VERSION 5.8 ;
BUSBITCHARS "[]" ;
DIVIDERCHAR "/" ;
UNITS
    DATABASE MICRONS 1000 ;
END UNITS

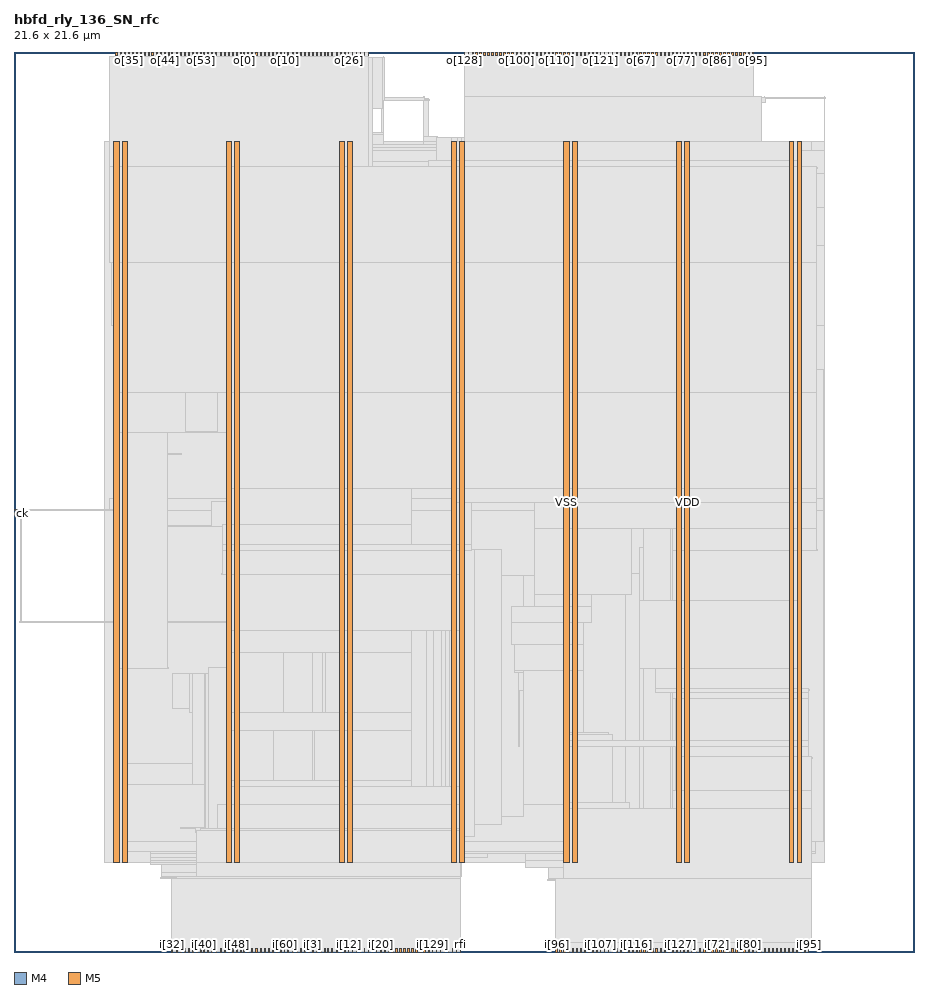
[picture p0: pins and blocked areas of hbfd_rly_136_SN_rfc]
MACRO hbfd_rly_136_SN_rfc
  FOREIGN hbfd_rly_136_SN_rfc 0 0 ;
  CLASS BLOCK ;
  SIZE 21.6 BY 21.6 ;
  PIN ck
    DIRECTION INPUT ;
    USE SIGNAL ;
    PORT
      LAYER M4 ;
        RECT  0 10.512 0.084 10.536 ;
    END
  END ck
  PIN i[0]
    DIRECTION INPUT ;
    USE SIGNAL ;
    PORT
      LAYER M5 ;
        RECT  6.864 0 6.888 0.084 ;
    END
  END i[0]
  PIN i[100]
    DIRECTION INPUT ;
    USE SIGNAL ;
    PORT
      LAYER M5 ;
        RECT  13.392 0 13.416 0.084 ;
    END
  END i[100]
  PIN i[101]
    DIRECTION INPUT ;
    USE SIGNAL ;
    PORT
      LAYER M5 ;
        RECT  13.488 0 13.512 0.084 ;
    END
  END i[101]
  PIN i[102]
    DIRECTION INPUT ;
    USE SIGNAL ;
    PORT
      LAYER M5 ;
        RECT  13.584 0 13.608 0.084 ;
    END
  END i[102]
  PIN i[103]
    DIRECTION INPUT ;
    USE SIGNAL ;
    PORT
      LAYER M5 ;
        RECT  13.68 0 13.704 0.084 ;
    END
  END i[103]
  PIN i[104]
    DIRECTION INPUT ;
    USE SIGNAL ;
    PORT
      LAYER M5 ;
        RECT  13.776 0 13.8 0.084 ;
    END
  END i[104]
  PIN i[105]
    DIRECTION INPUT ;
    USE SIGNAL ;
    PORT
      LAYER M5 ;
        RECT  13.872 0 13.896 0.084 ;
    END
  END i[105]
  PIN i[106]
    DIRECTION INPUT ;
    USE SIGNAL ;
    PORT
      LAYER M5 ;
        RECT  13.968 0 13.992 0.084 ;
    END
  END i[106]
  PIN i[107]
    DIRECTION INPUT ;
    USE SIGNAL ;
    PORT
      LAYER M5 ;
        RECT  14.064 0 14.088 0.084 ;
    END
  END i[107]
  PIN i[108]
    DIRECTION INPUT ;
    USE SIGNAL ;
    PORT
      LAYER M5 ;
        RECT  14.16 0 14.184 0.084 ;
    END
  END i[108]
  PIN i[109]
    DIRECTION INPUT ;
    USE SIGNAL ;
    PORT
      LAYER M5 ;
        RECT  14.256 0 14.28 0.084 ;
    END
  END i[109]
  PIN i[10]
    DIRECTION INPUT ;
    USE SIGNAL ;
    PORT
      LAYER M5 ;
        RECT  7.824 0 7.848 0.084 ;
    END
  END i[10]
  PIN i[110]
    DIRECTION INPUT ;
    USE SIGNAL ;
    PORT
      LAYER M5 ;
        RECT  14.352 0 14.376 0.084 ;
    END
  END i[110]
  PIN i[111]
    DIRECTION INPUT ;
    USE SIGNAL ;
    PORT
      LAYER M5 ;
        RECT  14.448 0 14.472 0.084 ;
    END
  END i[111]
  PIN i[112]
    DIRECTION INPUT ;
    USE SIGNAL ;
    PORT
      LAYER M5 ;
        RECT  14.544 0 14.568 0.084 ;
    END
  END i[112]
  PIN i[113]
    DIRECTION INPUT ;
    USE SIGNAL ;
    PORT
      LAYER M5 ;
        RECT  14.64 0 14.664 0.084 ;
    END
  END i[113]
  PIN i[114]
    DIRECTION INPUT ;
    USE SIGNAL ;
    PORT
      LAYER M5 ;
        RECT  14.736 0 14.76 0.084 ;
    END
  END i[114]
  PIN i[115]
    DIRECTION INPUT ;
    USE SIGNAL ;
    PORT
      LAYER M5 ;
        RECT  14.832 0 14.856 0.084 ;
    END
  END i[115]
  PIN i[116]
    DIRECTION INPUT ;
    USE SIGNAL ;
    PORT
      LAYER M5 ;
        RECT  14.928 0 14.952 0.084 ;
    END
  END i[116]
  PIN i[117]
    DIRECTION INPUT ;
    USE SIGNAL ;
    PORT
      LAYER M5 ;
        RECT  15.024 0 15.048 0.084 ;
    END
  END i[117]
  PIN i[118]
    DIRECTION INPUT ;
    USE SIGNAL ;
    PORT
      LAYER M5 ;
        RECT  15.12 0 15.144 0.084 ;
    END
  END i[118]
  PIN i[119]
    DIRECTION INPUT ;
    USE SIGNAL ;
    PORT
      LAYER M5 ;
        RECT  15.216 0 15.24 0.084 ;
    END
  END i[119]
  PIN i[11]
    DIRECTION INPUT ;
    USE SIGNAL ;
    PORT
      LAYER M5 ;
        RECT  7.92 0 7.944 0.084 ;
    END
  END i[11]
  PIN i[120]
    DIRECTION INPUT ;
    USE SIGNAL ;
    PORT
      LAYER M5 ;
        RECT  15.312 0 15.336 0.084 ;
    END
  END i[120]
  PIN i[121]
    DIRECTION INPUT ;
    USE SIGNAL ;
    PORT
      LAYER M5 ;
        RECT  15.408 0 15.432 0.084 ;
    END
  END i[121]
  PIN i[122]
    DIRECTION INPUT ;
    USE SIGNAL ;
    PORT
      LAYER M5 ;
        RECT  15.504 0 15.528 0.084 ;
    END
  END i[122]
  PIN i[123]
    DIRECTION INPUT ;
    USE SIGNAL ;
    PORT
      LAYER M5 ;
        RECT  15.6 0 15.624 0.084 ;
    END
  END i[123]
  PIN i[124]
    DIRECTION INPUT ;
    USE SIGNAL ;
    PORT
      LAYER M5 ;
        RECT  15.696 0 15.72 0.084 ;
    END
  END i[124]
  PIN i[125]
    DIRECTION INPUT ;
    USE SIGNAL ;
    PORT
      LAYER M5 ;
        RECT  15.792 0 15.816 0.084 ;
    END
  END i[125]
  PIN i[126]
    DIRECTION INPUT ;
    USE SIGNAL ;
    PORT
      LAYER M5 ;
        RECT  15.888 0 15.912 0.084 ;
    END
  END i[126]
  PIN i[127]
    DIRECTION INPUT ;
    USE SIGNAL ;
    PORT
      LAYER M5 ;
        RECT  15.984 0 16.008 0.084 ;
    END
  END i[127]
  PIN i[128]
    DIRECTION INPUT ;
    USE SIGNAL ;
    PORT
      LAYER M5 ;
        RECT  9.936 0 9.96 0.084 ;
    END
  END i[128]
  PIN i[129]
    DIRECTION INPUT ;
    USE SIGNAL ;
    PORT
      LAYER M5 ;
        RECT  10.032 0 10.056 0.084 ;
    END
  END i[129]
  PIN i[12]
    DIRECTION INPUT ;
    USE SIGNAL ;
    PORT
      LAYER M5 ;
        RECT  8.016 0 8.04 0.084 ;
    END
  END i[12]
  PIN i[130]
    DIRECTION INPUT ;
    USE SIGNAL ;
    PORT
      LAYER M5 ;
        RECT  10.128 0 10.152 0.084 ;
    END
  END i[130]
  PIN i[131]
    DIRECTION INPUT ;
    USE SIGNAL ;
    PORT
      LAYER M5 ;
        RECT  10.224 0 10.248 0.084 ;
    END
  END i[131]
  PIN i[132]
    DIRECTION INPUT ;
    USE SIGNAL ;
    PORT
      LAYER M5 ;
        RECT  10.32 0 10.344 0.084 ;
    END
  END i[132]
  PIN i[133]
    DIRECTION INPUT ;
    USE SIGNAL ;
    PORT
      LAYER M5 ;
        RECT  10.416 0 10.44 0.084 ;
    END
  END i[133]
  PIN i[134]
    DIRECTION INPUT ;
    USE SIGNAL ;
    PORT
      LAYER M5 ;
        RECT  10.512 0 10.536 0.084 ;
    END
  END i[134]
  PIN i[135]
    DIRECTION INPUT ;
    USE SIGNAL ;
    PORT
      LAYER M5 ;
        RECT  10.608 0 10.632 0.084 ;
    END
  END i[135]
  PIN i[13]
    DIRECTION INPUT ;
    USE SIGNAL ;
    PORT
      LAYER M5 ;
        RECT  8.112 0 8.136 0.084 ;
    END
  END i[13]
  PIN i[14]
    DIRECTION INPUT ;
    USE SIGNAL ;
    PORT
      LAYER M5 ;
        RECT  8.208 0 8.232 0.084 ;
    END
  END i[14]
  PIN i[15]
    DIRECTION INPUT ;
    USE SIGNAL ;
    PORT
      LAYER M5 ;
        RECT  8.304 0 8.328 0.084 ;
    END
  END i[15]
  PIN i[16]
    DIRECTION INPUT ;
    USE SIGNAL ;
    PORT
      LAYER M5 ;
        RECT  8.4 0 8.424 0.084 ;
    END
  END i[16]
  PIN i[17]
    DIRECTION INPUT ;
    USE SIGNAL ;
    PORT
      LAYER M5 ;
        RECT  8.496 0 8.52 0.084 ;
    END
  END i[17]
  PIN i[18]
    DIRECTION INPUT ;
    USE SIGNAL ;
    PORT
      LAYER M5 ;
        RECT  8.592 0 8.616 0.084 ;
    END
  END i[18]
  PIN i[19]
    DIRECTION INPUT ;
    USE SIGNAL ;
    PORT
      LAYER M5 ;
        RECT  8.688 0 8.712 0.084 ;
    END
  END i[19]
  PIN i[1]
    DIRECTION INPUT ;
    USE SIGNAL ;
    PORT
      LAYER M5 ;
        RECT  6.96 0 6.984 0.084 ;
    END
  END i[1]
  PIN i[20]
    DIRECTION INPUT ;
    USE SIGNAL ;
    PORT
      LAYER M5 ;
        RECT  8.784 0 8.808 0.084 ;
    END
  END i[20]
  PIN i[21]
    DIRECTION INPUT ;
    USE SIGNAL ;
    PORT
      LAYER M5 ;
        RECT  8.88 0 8.904 0.084 ;
    END
  END i[21]
  PIN i[22]
    DIRECTION INPUT ;
    USE SIGNAL ;
    PORT
      LAYER M5 ;
        RECT  8.976 0 9 0.084 ;
    END
  END i[22]
  PIN i[23]
    DIRECTION INPUT ;
    USE SIGNAL ;
    PORT
      LAYER M5 ;
        RECT  9.072 0 9.096 0.084 ;
    END
  END i[23]
  PIN i[24]
    DIRECTION INPUT ;
    USE SIGNAL ;
    PORT
      LAYER M5 ;
        RECT  9.168 0 9.192 0.084 ;
    END
  END i[24]
  PIN i[25]
    DIRECTION INPUT ;
    USE SIGNAL ;
    PORT
      LAYER M5 ;
        RECT  9.264 0 9.288 0.084 ;
    END
  END i[25]
  PIN i[26]
    DIRECTION INPUT ;
    USE SIGNAL ;
    PORT
      LAYER M5 ;
        RECT  9.36 0 9.384 0.084 ;
    END
  END i[26]
  PIN i[27]
    DIRECTION INPUT ;
    USE SIGNAL ;
    PORT
      LAYER M5 ;
        RECT  9.456 0 9.48 0.084 ;
    END
  END i[27]
  PIN i[28]
    DIRECTION INPUT ;
    USE SIGNAL ;
    PORT
      LAYER M5 ;
        RECT  9.552 0 9.576 0.084 ;
    END
  END i[28]
  PIN i[29]
    DIRECTION INPUT ;
    USE SIGNAL ;
    PORT
      LAYER M5 ;
        RECT  9.648 0 9.672 0.084 ;
    END
  END i[29]
  PIN i[2]
    DIRECTION INPUT ;
    USE SIGNAL ;
    PORT
      LAYER M5 ;
        RECT  7.056 0 7.08 0.084 ;
    END
  END i[2]
  PIN i[30]
    DIRECTION INPUT ;
    USE SIGNAL ;
    PORT
      LAYER M5 ;
        RECT  9.744 0 9.768 0.084 ;
    END
  END i[30]
  PIN i[31]
    DIRECTION INPUT ;
    USE SIGNAL ;
    PORT
      LAYER M5 ;
        RECT  9.84 0 9.864 0.084 ;
    END
  END i[31]
  PIN i[32]
    DIRECTION INPUT ;
    USE SIGNAL ;
    PORT
      LAYER M5 ;
        RECT  3.792 0 3.816 0.084 ;
    END
  END i[32]
  PIN i[33]
    DIRECTION INPUT ;
    USE SIGNAL ;
    PORT
      LAYER M5 ;
        RECT  3.888 0 3.912 0.084 ;
    END
  END i[33]
  PIN i[34]
    DIRECTION INPUT ;
    USE SIGNAL ;
    PORT
      LAYER M5 ;
        RECT  3.984 0 4.008 0.084 ;
    END
  END i[34]
  PIN i[35]
    DIRECTION INPUT ;
    USE SIGNAL ;
    PORT
      LAYER M5 ;
        RECT  4.08 0 4.104 0.084 ;
    END
  END i[35]
  PIN i[36]
    DIRECTION INPUT ;
    USE SIGNAL ;
    PORT
      LAYER M5 ;
        RECT  4.176 0 4.2 0.084 ;
    END
  END i[36]
  PIN i[37]
    DIRECTION INPUT ;
    USE SIGNAL ;
    PORT
      LAYER M5 ;
        RECT  4.272 0 4.296 0.084 ;
    END
  END i[37]
  PIN i[38]
    DIRECTION INPUT ;
    USE SIGNAL ;
    PORT
      LAYER M5 ;
        RECT  4.368 0 4.392 0.084 ;
    END
  END i[38]
  PIN i[39]
    DIRECTION INPUT ;
    USE SIGNAL ;
    PORT
      LAYER M5 ;
        RECT  4.464 0 4.488 0.084 ;
    END
  END i[39]
  PIN i[3]
    DIRECTION INPUT ;
    USE SIGNAL ;
    PORT
      LAYER M5 ;
        RECT  7.152 0 7.176 0.084 ;
    END
  END i[3]
  PIN i[40]
    DIRECTION INPUT ;
    USE SIGNAL ;
    PORT
      LAYER M5 ;
        RECT  4.56 0 4.584 0.084 ;
    END
  END i[40]
  PIN i[41]
    DIRECTION INPUT ;
    USE SIGNAL ;
    PORT
      LAYER M5 ;
        RECT  4.656 0 4.68 0.084 ;
    END
  END i[41]
  PIN i[42]
    DIRECTION INPUT ;
    USE SIGNAL ;
    PORT
      LAYER M5 ;
        RECT  4.752 0 4.776 0.084 ;
    END
  END i[42]
  PIN i[43]
    DIRECTION INPUT ;
    USE SIGNAL ;
    PORT
      LAYER M5 ;
        RECT  4.848 0 4.872 0.084 ;
    END
  END i[43]
  PIN i[44]
    DIRECTION INPUT ;
    USE SIGNAL ;
    PORT
      LAYER M5 ;
        RECT  4.944 0 4.968 0.084 ;
    END
  END i[44]
  PIN i[45]
    DIRECTION INPUT ;
    USE SIGNAL ;
    PORT
      LAYER M5 ;
        RECT  5.04 0 5.064 0.084 ;
    END
  END i[45]
  PIN i[46]
    DIRECTION INPUT ;
    USE SIGNAL ;
    PORT
      LAYER M5 ;
        RECT  5.136 0 5.16 0.084 ;
    END
  END i[46]
  PIN i[47]
    DIRECTION INPUT ;
    USE SIGNAL ;
    PORT
      LAYER M5 ;
        RECT  5.232 0 5.256 0.084 ;
    END
  END i[47]
  PIN i[48]
    DIRECTION INPUT ;
    USE SIGNAL ;
    PORT
      LAYER M5 ;
        RECT  5.328 0 5.352 0.084 ;
    END
  END i[48]
  PIN i[49]
    DIRECTION INPUT ;
    USE SIGNAL ;
    PORT
      LAYER M5 ;
        RECT  5.424 0 5.448 0.084 ;
    END
  END i[49]
  PIN i[4]
    DIRECTION INPUT ;
    USE SIGNAL ;
    PORT
      LAYER M5 ;
        RECT  7.248 0 7.272 0.084 ;
    END
  END i[4]
  PIN i[50]
    DIRECTION INPUT ;
    USE SIGNAL ;
    PORT
      LAYER M5 ;
        RECT  5.52 0 5.544 0.084 ;
    END
  END i[50]
  PIN i[51]
    DIRECTION INPUT ;
    USE SIGNAL ;
    PORT
      LAYER M5 ;
        RECT  5.616 0 5.64 0.084 ;
    END
  END i[51]
  PIN i[52]
    DIRECTION INPUT ;
    USE SIGNAL ;
    PORT
      LAYER M5 ;
        RECT  5.712 0 5.736 0.084 ;
    END
  END i[52]
  PIN i[53]
    DIRECTION INPUT ;
    USE SIGNAL ;
    PORT
      LAYER M5 ;
        RECT  5.808 0 5.832 0.084 ;
    END
  END i[53]
  PIN i[54]
    DIRECTION INPUT ;
    USE SIGNAL ;
    PORT
      LAYER M5 ;
        RECT  5.904 0 5.928 0.084 ;
    END
  END i[54]
  PIN i[55]
    DIRECTION INPUT ;
    USE SIGNAL ;
    PORT
      LAYER M5 ;
        RECT  6 0 6.024 0.084 ;
    END
  END i[55]
  PIN i[56]
    DIRECTION INPUT ;
    USE SIGNAL ;
    PORT
      LAYER M5 ;
        RECT  6.096 0 6.12 0.084 ;
    END
  END i[56]
  PIN i[57]
    DIRECTION INPUT ;
    USE SIGNAL ;
    PORT
      LAYER M5 ;
        RECT  6.192 0 6.216 0.084 ;
    END
  END i[57]
  PIN i[58]
    DIRECTION INPUT ;
    USE SIGNAL ;
    PORT
      LAYER M5 ;
        RECT  6.288 0 6.312 0.084 ;
    END
  END i[58]
  PIN i[59]
    DIRECTION INPUT ;
    USE SIGNAL ;
    PORT
      LAYER M5 ;
        RECT  6.384 0 6.408 0.084 ;
    END
  END i[59]
  PIN i[5]
    DIRECTION INPUT ;
    USE SIGNAL ;
    PORT
      LAYER M5 ;
        RECT  7.344 0 7.368 0.084 ;
    END
  END i[5]
  PIN i[60]
    DIRECTION INPUT ;
    USE SIGNAL ;
    PORT
      LAYER M5 ;
        RECT  6.48 0 6.504 0.084 ;
    END
  END i[60]
  PIN i[61]
    DIRECTION INPUT ;
    USE SIGNAL ;
    PORT
      LAYER M5 ;
        RECT  6.576 0 6.6 0.084 ;
    END
  END i[61]
  PIN i[62]
    DIRECTION INPUT ;
    USE SIGNAL ;
    PORT
      LAYER M5 ;
        RECT  6.672 0 6.696 0.084 ;
    END
  END i[62]
  PIN i[63]
    DIRECTION INPUT ;
    USE SIGNAL ;
    PORT
      LAYER M5 ;
        RECT  6.768 0 6.792 0.084 ;
    END
  END i[63]
  PIN i[64]
    DIRECTION INPUT ;
    USE SIGNAL ;
    PORT
      LAYER M5 ;
        RECT  16.08 0 16.104 0.084 ;
    END
  END i[64]
  PIN i[65]
    DIRECTION INPUT ;
    USE SIGNAL ;
    PORT
      LAYER M5 ;
        RECT  16.176 0 16.2 0.084 ;
    END
  END i[65]
  PIN i[66]
    DIRECTION INPUT ;
    USE SIGNAL ;
    PORT
      LAYER M5 ;
        RECT  16.272 0 16.296 0.084 ;
    END
  END i[66]
  PIN i[67]
    DIRECTION INPUT ;
    USE SIGNAL ;
    PORT
      LAYER M5 ;
        RECT  16.368 0 16.392 0.084 ;
    END
  END i[67]
  PIN i[68]
    DIRECTION INPUT ;
    USE SIGNAL ;
    PORT
      LAYER M5 ;
        RECT  16.464 0 16.488 0.084 ;
    END
  END i[68]
  PIN i[69]
    DIRECTION INPUT ;
    USE SIGNAL ;
    PORT
      LAYER M5 ;
        RECT  16.56 0 16.584 0.084 ;
    END
  END i[69]
  PIN i[6]
    DIRECTION INPUT ;
    USE SIGNAL ;
    PORT
      LAYER M5 ;
        RECT  7.44 0 7.464 0.084 ;
    END
  END i[6]
  PIN i[70]
    DIRECTION INPUT ;
    USE SIGNAL ;
    PORT
      LAYER M5 ;
        RECT  16.656 0 16.68 0.084 ;
    END
  END i[70]
  PIN i[71]
    DIRECTION INPUT ;
    USE SIGNAL ;
    PORT
      LAYER M5 ;
        RECT  16.752 0 16.776 0.084 ;
    END
  END i[71]
  PIN i[72]
    DIRECTION INPUT ;
    USE SIGNAL ;
    PORT
      LAYER M5 ;
        RECT  16.848 0 16.872 0.084 ;
    END
  END i[72]
  PIN i[73]
    DIRECTION INPUT ;
    USE SIGNAL ;
    PORT
      LAYER M5 ;
        RECT  16.944 0 16.968 0.084 ;
    END
  END i[73]
  PIN i[74]
    DIRECTION INPUT ;
    USE SIGNAL ;
    PORT
      LAYER M5 ;
        RECT  17.04 0 17.064 0.084 ;
    END
  END i[74]
  PIN i[75]
    DIRECTION INPUT ;
    USE SIGNAL ;
    PORT
      LAYER M5 ;
        RECT  17.136 0 17.16 0.084 ;
    END
  END i[75]
  PIN i[76]
    DIRECTION INPUT ;
    USE SIGNAL ;
    PORT
      LAYER M5 ;
        RECT  17.232 0 17.256 0.084 ;
    END
  END i[76]
  PIN i[77]
    DIRECTION INPUT ;
    USE SIGNAL ;
    PORT
      LAYER M5 ;
        RECT  17.328 0 17.352 0.084 ;
    END
  END i[77]
  PIN i[78]
    DIRECTION INPUT ;
    USE SIGNAL ;
    PORT
      LAYER M5 ;
        RECT  17.424 0 17.448 0.084 ;
    END
  END i[78]
  PIN i[79]
    DIRECTION INPUT ;
    USE SIGNAL ;
    PORT
      LAYER M5 ;
        RECT  17.52 0 17.544 0.084 ;
    END
  END i[79]
  PIN i[7]
    DIRECTION INPUT ;
    USE SIGNAL ;
    PORT
      LAYER M5 ;
        RECT  7.536 0 7.56 0.084 ;
    END
  END i[7]
  PIN i[80]
    DIRECTION INPUT ;
    USE SIGNAL ;
    PORT
      LAYER M5 ;
        RECT  17.616 0 17.64 0.084 ;
    END
  END i[80]
  PIN i[81]
    DIRECTION INPUT ;
    USE SIGNAL ;
    PORT
      LAYER M5 ;
        RECT  17.712 0 17.736 0.084 ;
    END
  END i[81]
  PIN i[82]
    DIRECTION INPUT ;
    USE SIGNAL ;
    PORT
      LAYER M5 ;
        RECT  17.808 0 17.832 0.084 ;
    END
  END i[82]
  PIN i[83]
    DIRECTION INPUT ;
    USE SIGNAL ;
    PORT
      LAYER M5 ;
        RECT  17.904 0 17.928 0.084 ;
    END
  END i[83]
  PIN i[84]
    DIRECTION INPUT ;
    USE SIGNAL ;
    PORT
      LAYER M5 ;
        RECT  18 0 18.024 0.084 ;
    END
  END i[84]
  PIN i[85]
    DIRECTION INPUT ;
    USE SIGNAL ;
    PORT
      LAYER M5 ;
        RECT  18.096 0 18.12 0.084 ;
    END
  END i[85]
  PIN i[86]
    DIRECTION INPUT ;
    USE SIGNAL ;
    PORT
      LAYER M5 ;
        RECT  18.192 0 18.216 0.084 ;
    END
  END i[86]
  PIN i[87]
    DIRECTION INPUT ;
    USE SIGNAL ;
    PORT
      LAYER M5 ;
        RECT  18.288 0 18.312 0.084 ;
    END
  END i[87]
  PIN i[88]
    DIRECTION INPUT ;
    USE SIGNAL ;
    PORT
      LAYER M5 ;
        RECT  18.384 0 18.408 0.084 ;
    END
  END i[88]
  PIN i[89]
    DIRECTION INPUT ;
    USE SIGNAL ;
    PORT
      LAYER M5 ;
        RECT  18.48 0 18.504 0.084 ;
    END
  END i[89]
  PIN i[8]
    DIRECTION INPUT ;
    USE SIGNAL ;
    PORT
      LAYER M5 ;
        RECT  7.632 0 7.656 0.084 ;
    END
  END i[8]
  PIN i[90]
    DIRECTION INPUT ;
    USE SIGNAL ;
    PORT
      LAYER M5 ;
        RECT  18.576 0 18.6 0.084 ;
    END
  END i[90]
  PIN i[91]
    DIRECTION INPUT ;
    USE SIGNAL ;
    PORT
      LAYER M5 ;
        RECT  18.672 0 18.696 0.084 ;
    END
  END i[91]
  PIN i[92]
    DIRECTION INPUT ;
    USE SIGNAL ;
    PORT
      LAYER M5 ;
        RECT  18.768 0 18.792 0.084 ;
    END
  END i[92]
  PIN i[93]
    DIRECTION INPUT ;
    USE SIGNAL ;
    PORT
      LAYER M5 ;
        RECT  18.864 0 18.888 0.084 ;
    END
  END i[93]
  PIN i[94]
    DIRECTION INPUT ;
    USE SIGNAL ;
    PORT
      LAYER M5 ;
        RECT  18.96 0 18.984 0.084 ;
    END
  END i[94]
  PIN i[95]
    DIRECTION INPUT ;
    USE SIGNAL ;
    PORT
      LAYER M5 ;
        RECT  19.056 0 19.08 0.084 ;
    END
  END i[95]
  PIN i[96]
    DIRECTION INPUT ;
    USE SIGNAL ;
    PORT
      LAYER M5 ;
        RECT  13.008 0 13.032 0.084 ;
    END
  END i[96]
  PIN i[97]
    DIRECTION INPUT ;
    USE SIGNAL ;
    PORT
      LAYER M5 ;
        RECT  13.104 0 13.128 0.084 ;
    END
  END i[97]
  PIN i[98]
    DIRECTION INPUT ;
    USE SIGNAL ;
    PORT
      LAYER M5 ;
        RECT  13.2 0 13.224 0.084 ;
    END
  END i[98]
  PIN i[99]
    DIRECTION INPUT ;
    USE SIGNAL ;
    PORT
      LAYER M5 ;
        RECT  13.296 0 13.32 0.084 ;
    END
  END i[99]
  PIN i[9]
    DIRECTION INPUT ;
    USE SIGNAL ;
    PORT
      LAYER M5 ;
        RECT  7.728 0 7.752 0.084 ;
    END
  END i[9]
  PIN o[0]
    DIRECTION OUTPUT ;
    USE SIGNAL ;
    PORT
      LAYER M5 ;
        RECT  5.52 21.516 5.544 21.6 ;
    END
  END o[0]
  PIN o[100]
    DIRECTION OUTPUT ;
    USE SIGNAL ;
    PORT
      LAYER M5 ;
        RECT  12.048 21.516 12.072 21.6 ;
    END
  END o[100]
  PIN o[101]
    DIRECTION OUTPUT ;
    USE SIGNAL ;
    PORT
      LAYER M5 ;
        RECT  12.144 21.516 12.168 21.6 ;
    END
  END o[101]
  PIN o[102]
    DIRECTION OUTPUT ;
    USE SIGNAL ;
    PORT
      LAYER M5 ;
        RECT  12.24 21.516 12.264 21.6 ;
    END
  END o[102]
  PIN o[103]
    DIRECTION OUTPUT ;
    USE SIGNAL ;
    PORT
      LAYER M5 ;
        RECT  12.336 21.516 12.36 21.6 ;
    END
  END o[103]
  PIN o[104]
    DIRECTION OUTPUT ;
    USE SIGNAL ;
    PORT
      LAYER M5 ;
        RECT  12.432 21.516 12.456 21.6 ;
    END
  END o[104]
  PIN o[105]
    DIRECTION OUTPUT ;
    USE SIGNAL ;
    PORT
      LAYER M5 ;
        RECT  12.528 21.516 12.552 21.6 ;
    END
  END o[105]
  PIN o[106]
    DIRECTION OUTPUT ;
    USE SIGNAL ;
    PORT
      LAYER M5 ;
        RECT  12.624 21.516 12.648 21.6 ;
    END
  END o[106]
  PIN o[107]
    DIRECTION OUTPUT ;
    USE SIGNAL ;
    PORT
      LAYER M5 ;
        RECT  12.72 21.516 12.744 21.6 ;
    END
  END o[107]
  PIN o[108]
    DIRECTION OUTPUT ;
    USE SIGNAL ;
    PORT
      LAYER M5 ;
        RECT  12.816 21.516 12.84 21.6 ;
    END
  END o[108]
  PIN o[109]
    DIRECTION OUTPUT ;
    USE SIGNAL ;
    PORT
      LAYER M5 ;
        RECT  12.912 21.516 12.936 21.6 ;
    END
  END o[109]
  PIN o[10]
    DIRECTION OUTPUT ;
    USE SIGNAL ;
    PORT
      LAYER M5 ;
        RECT  6.48 21.516 6.504 21.6 ;
    END
  END o[10]
  PIN o[110]
    DIRECTION OUTPUT ;
    USE SIGNAL ;
    PORT
      LAYER M5 ;
        RECT  13.008 21.516 13.032 21.6 ;
    END
  END o[110]
  PIN o[111]
    DIRECTION OUTPUT ;
    USE SIGNAL ;
    PORT
      LAYER M5 ;
        RECT  13.104 21.516 13.128 21.6 ;
    END
  END o[111]
  PIN o[112]
    DIRECTION OUTPUT ;
    USE SIGNAL ;
    PORT
      LAYER M5 ;
        RECT  13.2 21.516 13.224 21.6 ;
    END
  END o[112]
  PIN o[113]
    DIRECTION OUTPUT ;
    USE SIGNAL ;
    PORT
      LAYER M5 ;
        RECT  13.296 21.516 13.32 21.6 ;
    END
  END o[113]
  PIN o[114]
    DIRECTION OUTPUT ;
    USE SIGNAL ;
    PORT
      LAYER M5 ;
        RECT  13.392 21.516 13.416 21.6 ;
    END
  END o[114]
  PIN o[115]
    DIRECTION OUTPUT ;
    USE SIGNAL ;
    PORT
      LAYER M5 ;
        RECT  13.488 21.516 13.512 21.6 ;
    END
  END o[115]
  PIN o[116]
    DIRECTION OUTPUT ;
    USE SIGNAL ;
    PORT
      LAYER M5 ;
        RECT  13.584 21.516 13.608 21.6 ;
    END
  END o[116]
  PIN o[117]
    DIRECTION OUTPUT ;
    USE SIGNAL ;
    PORT
      LAYER M5 ;
        RECT  13.68 21.516 13.704 21.6 ;
    END
  END o[117]
  PIN o[118]
    DIRECTION OUTPUT ;
    USE SIGNAL ;
    PORT
      LAYER M5 ;
        RECT  13.776 21.516 13.8 21.6 ;
    END
  END o[118]
  PIN o[119]
    DIRECTION OUTPUT ;
    USE SIGNAL ;
    PORT
      LAYER M5 ;
        RECT  13.872 21.516 13.896 21.6 ;
    END
  END o[119]
  PIN o[11]
    DIRECTION OUTPUT ;
    USE SIGNAL ;
    PORT
      LAYER M5 ;
        RECT  6.576 21.516 6.6 21.6 ;
    END
  END o[11]
  PIN o[120]
    DIRECTION OUTPUT ;
    USE SIGNAL ;
    PORT
      LAYER M5 ;
        RECT  13.968 21.516 13.992 21.6 ;
    END
  END o[120]
  PIN o[121]
    DIRECTION OUTPUT ;
    USE SIGNAL ;
    PORT
      LAYER M5 ;
        RECT  14.064 21.516 14.088 21.6 ;
    END
  END o[121]
  PIN o[122]
    DIRECTION OUTPUT ;
    USE SIGNAL ;
    PORT
      LAYER M5 ;
        RECT  14.16 21.516 14.184 21.6 ;
    END
  END o[122]
  PIN o[123]
    DIRECTION OUTPUT ;
    USE SIGNAL ;
    PORT
      LAYER M5 ;
        RECT  14.256 21.516 14.28 21.6 ;
    END
  END o[123]
  PIN o[124]
    DIRECTION OUTPUT ;
    USE SIGNAL ;
    PORT
      LAYER M5 ;
        RECT  14.352 21.516 14.376 21.6 ;
    END
  END o[124]
  PIN o[125]
    DIRECTION OUTPUT ;
    USE SIGNAL ;
    PORT
      LAYER M5 ;
        RECT  14.448 21.516 14.472 21.6 ;
    END
  END o[125]
  PIN o[126]
    DIRECTION OUTPUT ;
    USE SIGNAL ;
    PORT
      LAYER M5 ;
        RECT  14.544 21.516 14.568 21.6 ;
    END
  END o[126]
  PIN o[127]
    DIRECTION OUTPUT ;
    USE SIGNAL ;
    PORT
      LAYER M5 ;
        RECT  14.64 21.516 14.664 21.6 ;
    END
  END o[127]
  PIN o[128]
    DIRECTION OUTPUT ;
    USE SIGNAL ;
    PORT
      LAYER M5 ;
        RECT  10.8 21.516 10.824 21.6 ;
    END
  END o[128]
  PIN o[129]
    DIRECTION OUTPUT ;
    USE SIGNAL ;
    PORT
      LAYER M5 ;
        RECT  10.896 21.516 10.92 21.6 ;
    END
  END o[129]
  PIN o[12]
    DIRECTION OUTPUT ;
    USE SIGNAL ;
    PORT
      LAYER M5 ;
        RECT  6.672 21.516 6.696 21.6 ;
    END
  END o[12]
  PIN o[130]
    DIRECTION OUTPUT ;
    USE SIGNAL ;
    PORT
      LAYER M5 ;
        RECT  10.992 21.516 11.016 21.6 ;
    END
  END o[130]
  PIN o[131]
    DIRECTION OUTPUT ;
    USE SIGNAL ;
    PORT
      LAYER M5 ;
        RECT  11.088 21.516 11.112 21.6 ;
    END
  END o[131]
  PIN o[132]
    DIRECTION OUTPUT ;
    USE SIGNAL ;
    PORT
      LAYER M5 ;
        RECT  11.184 21.516 11.208 21.6 ;
    END
  END o[132]
  PIN o[133]
    DIRECTION OUTPUT ;
    USE SIGNAL ;
    PORT
      LAYER M5 ;
        RECT  11.28 21.516 11.304 21.6 ;
    END
  END o[133]
  PIN o[134]
    DIRECTION OUTPUT ;
    USE SIGNAL ;
    PORT
      LAYER M5 ;
        RECT  11.376 21.516 11.4 21.6 ;
    END
  END o[134]
  PIN o[135]
    DIRECTION OUTPUT ;
    USE SIGNAL ;
    PORT
      LAYER M5 ;
        RECT  11.472 21.516 11.496 21.6 ;
    END
  END o[135]
  PIN o[13]
    DIRECTION OUTPUT ;
    USE SIGNAL ;
    PORT
      LAYER M5 ;
        RECT  6.768 21.516 6.792 21.6 ;
    END
  END o[13]
  PIN o[14]
    DIRECTION OUTPUT ;
    USE SIGNAL ;
    PORT
      LAYER M5 ;
        RECT  6.864 21.516 6.888 21.6 ;
    END
  END o[14]
  PIN o[15]
    DIRECTION OUTPUT ;
    USE SIGNAL ;
    PORT
      LAYER M5 ;
        RECT  6.96 21.516 6.984 21.6 ;
    END
  END o[15]
  PIN o[16]
    DIRECTION OUTPUT ;
    USE SIGNAL ;
    PORT
      LAYER M5 ;
        RECT  7.056 21.516 7.08 21.6 ;
    END
  END o[16]
  PIN o[17]
    DIRECTION OUTPUT ;
    USE SIGNAL ;
    PORT
      LAYER M5 ;
        RECT  7.152 21.516 7.176 21.6 ;
    END
  END o[17]
  PIN o[18]
    DIRECTION OUTPUT ;
    USE SIGNAL ;
    PORT
      LAYER M5 ;
        RECT  7.248 21.516 7.272 21.6 ;
    END
  END o[18]
  PIN o[19]
    DIRECTION OUTPUT ;
    USE SIGNAL ;
    PORT
      LAYER M5 ;
        RECT  7.344 21.516 7.368 21.6 ;
    END
  END o[19]
  PIN o[1]
    DIRECTION OUTPUT ;
    USE SIGNAL ;
    PORT
      LAYER M5 ;
        RECT  5.616 21.516 5.64 21.6 ;
    END
  END o[1]
  PIN o[20]
    DIRECTION OUTPUT ;
    USE SIGNAL ;
    PORT
      LAYER M5 ;
        RECT  7.44 21.516 7.464 21.6 ;
    END
  END o[20]
  PIN o[21]
    DIRECTION OUTPUT ;
    USE SIGNAL ;
    PORT
      LAYER M5 ;
        RECT  7.536 21.516 7.56 21.6 ;
    END
  END o[21]
  PIN o[22]
    DIRECTION OUTPUT ;
    USE SIGNAL ;
    PORT
      LAYER M5 ;
        RECT  7.632 21.516 7.656 21.6 ;
    END
  END o[22]
  PIN o[23]
    DIRECTION OUTPUT ;
    USE SIGNAL ;
    PORT
      LAYER M5 ;
        RECT  7.728 21.516 7.752 21.6 ;
    END
  END o[23]
  PIN o[24]
    DIRECTION OUTPUT ;
    USE SIGNAL ;
    PORT
      LAYER M5 ;
        RECT  7.824 21.516 7.848 21.6 ;
    END
  END o[24]
  PIN o[25]
    DIRECTION OUTPUT ;
    USE SIGNAL ;
    PORT
      LAYER M5 ;
        RECT  7.92 21.516 7.944 21.6 ;
    END
  END o[25]
  PIN o[26]
    DIRECTION OUTPUT ;
    USE SIGNAL ;
    PORT
      LAYER M5 ;
        RECT  8.016 21.516 8.04 21.6 ;
    END
  END o[26]
  PIN o[27]
    DIRECTION OUTPUT ;
    USE SIGNAL ;
    PORT
      LAYER M5 ;
        RECT  8.112 21.516 8.136 21.6 ;
    END
  END o[27]
  PIN o[28]
    DIRECTION OUTPUT ;
    USE SIGNAL ;
    PORT
      LAYER M5 ;
        RECT  8.208 21.516 8.232 21.6 ;
    END
  END o[28]
  PIN o[29]
    DIRECTION OUTPUT ;
    USE SIGNAL ;
    PORT
      LAYER M5 ;
        RECT  8.304 21.516 8.328 21.6 ;
    END
  END o[29]
  PIN o[2]
    DIRECTION OUTPUT ;
    USE SIGNAL ;
    PORT
      LAYER M5 ;
        RECT  5.712 21.516 5.736 21.6 ;
    END
  END o[2]
  PIN o[30]
    DIRECTION OUTPUT ;
    USE SIGNAL ;
    PORT
      LAYER M5 ;
        RECT  8.4 21.516 8.424 21.6 ;
    END
  END o[30]
  PIN o[31]
    DIRECTION OUTPUT ;
    USE SIGNAL ;
    PORT
      LAYER M5 ;
        RECT  8.496 21.516 8.52 21.6 ;
    END
  END o[31]
  PIN o[32]
    DIRECTION OUTPUT ;
    USE SIGNAL ;
    PORT
      LAYER M5 ;
        RECT  2.448 21.516 2.472 21.6 ;
    END
  END o[32]
  PIN o[33]
    DIRECTION OUTPUT ;
    USE SIGNAL ;
    PORT
      LAYER M5 ;
        RECT  2.544 21.516 2.568 21.6 ;
    END
  END o[33]
  PIN o[34]
    DIRECTION OUTPUT ;
    USE SIGNAL ;
    PORT
      LAYER M5 ;
        RECT  2.64 21.516 2.664 21.6 ;
    END
  END o[34]
  PIN o[35]
    DIRECTION OUTPUT ;
    USE SIGNAL ;
    PORT
      LAYER M5 ;
        RECT  2.736 21.516 2.76 21.6 ;
    END
  END o[35]
  PIN o[36]
    DIRECTION OUTPUT ;
    USE SIGNAL ;
    PORT
      LAYER M5 ;
        RECT  2.832 21.516 2.856 21.6 ;
    END
  END o[36]
  PIN o[37]
    DIRECTION OUTPUT ;
    USE SIGNAL ;
    PORT
      LAYER M5 ;
        RECT  2.928 21.516 2.952 21.6 ;
    END
  END o[37]
  PIN o[38]
    DIRECTION OUTPUT ;
    USE SIGNAL ;
    PORT
      LAYER M5 ;
        RECT  3.024 21.516 3.048 21.6 ;
    END
  END o[38]
  PIN o[39]
    DIRECTION OUTPUT ;
    USE SIGNAL ;
    PORT
      LAYER M5 ;
        RECT  3.12 21.516 3.144 21.6 ;
    END
  END o[39]
  PIN o[3]
    DIRECTION OUTPUT ;
    USE SIGNAL ;
    PORT
      LAYER M5 ;
        RECT  5.808 21.516 5.832 21.6 ;
    END
  END o[3]
  PIN o[40]
    DIRECTION OUTPUT ;
    USE SIGNAL ;
    PORT
      LAYER M5 ;
        RECT  3.216 21.516 3.24 21.6 ;
    END
  END o[40]
  PIN o[41]
    DIRECTION OUTPUT ;
    USE SIGNAL ;
    PORT
      LAYER M5 ;
        RECT  3.312 21.516 3.336 21.6 ;
    END
  END o[41]
  PIN o[42]
    DIRECTION OUTPUT ;
    USE SIGNAL ;
    PORT
      LAYER M5 ;
        RECT  3.408 21.516 3.432 21.6 ;
    END
  END o[42]
  PIN o[43]
    DIRECTION OUTPUT ;
    USE SIGNAL ;
    PORT
      LAYER M5 ;
        RECT  3.504 21.516 3.528 21.6 ;
    END
  END o[43]
  PIN o[44]
    DIRECTION OUTPUT ;
    USE SIGNAL ;
    PORT
      LAYER M5 ;
        RECT  3.6 21.516 3.624 21.6 ;
    END
  END o[44]
  PIN o[45]
    DIRECTION OUTPUT ;
    USE SIGNAL ;
    PORT
      LAYER M5 ;
        RECT  3.696 21.516 3.72 21.6 ;
    END
  END o[45]
  PIN o[46]
    DIRECTION OUTPUT ;
    USE SIGNAL ;
    PORT
      LAYER M5 ;
        RECT  3.792 21.516 3.816 21.6 ;
    END
  END o[46]
  PIN o[47]
    DIRECTION OUTPUT ;
    USE SIGNAL ;
    PORT
      LAYER M5 ;
        RECT  3.888 21.516 3.912 21.6 ;
    END
  END o[47]
  PIN o[48]
    DIRECTION OUTPUT ;
    USE SIGNAL ;
    PORT
      LAYER M5 ;
        RECT  3.984 21.516 4.008 21.6 ;
    END
  END o[48]
  PIN o[49]
    DIRECTION OUTPUT ;
    USE SIGNAL ;
    PORT
      LAYER M5 ;
        RECT  4.08 21.516 4.104 21.6 ;
    END
  END o[49]
  PIN o[4]
    DIRECTION OUTPUT ;
    USE SIGNAL ;
    PORT
      LAYER M5 ;
        RECT  5.904 21.516 5.928 21.6 ;
    END
  END o[4]
  PIN o[50]
    DIRECTION OUTPUT ;
    USE SIGNAL ;
    PORT
      LAYER M5 ;
        RECT  4.176 21.516 4.2 21.6 ;
    END
  END o[50]
  PIN o[51]
    DIRECTION OUTPUT ;
    USE SIGNAL ;
    PORT
      LAYER M5 ;
        RECT  4.272 21.516 4.296 21.6 ;
    END
  END o[51]
  PIN o[52]
    DIRECTION OUTPUT ;
    USE SIGNAL ;
    PORT
      LAYER M5 ;
        RECT  4.368 21.516 4.392 21.6 ;
    END
  END o[52]
  PIN o[53]
    DIRECTION OUTPUT ;
    USE SIGNAL ;
    PORT
      LAYER M5 ;
        RECT  4.464 21.516 4.488 21.6 ;
    END
  END o[53]
  PIN o[54]
    DIRECTION OUTPUT ;
    USE SIGNAL ;
    PORT
      LAYER M5 ;
        RECT  4.56 21.516 4.584 21.6 ;
    END
  END o[54]
  PIN o[55]
    DIRECTION OUTPUT ;
    USE SIGNAL ;
    PORT
      LAYER M5 ;
        RECT  4.656 21.516 4.68 21.6 ;
    END
  END o[55]
  PIN o[56]
    DIRECTION OUTPUT ;
    USE SIGNAL ;
    PORT
      LAYER M5 ;
        RECT  4.752 21.516 4.776 21.6 ;
    END
  END o[56]
  PIN o[57]
    DIRECTION OUTPUT ;
    USE SIGNAL ;
    PORT
      LAYER M5 ;
        RECT  4.848 21.516 4.872 21.6 ;
    END
  END o[57]
  PIN o[58]
    DIRECTION OUTPUT ;
    USE SIGNAL ;
    PORT
      LAYER M5 ;
        RECT  4.944 21.516 4.968 21.6 ;
    END
  END o[58]
  PIN o[59]
    DIRECTION OUTPUT ;
    USE SIGNAL ;
    PORT
      LAYER M5 ;
        RECT  5.04 21.516 5.064 21.6 ;
    END
  END o[59]
  PIN o[5]
    DIRECTION OUTPUT ;
    USE SIGNAL ;
    PORT
      LAYER M5 ;
        RECT  6 21.516 6.024 21.6 ;
    END
  END o[5]
  PIN o[60]
    DIRECTION OUTPUT ;
    USE SIGNAL ;
    PORT
      LAYER M5 ;
        RECT  5.136 21.516 5.16 21.6 ;
    END
  END o[60]
  PIN o[61]
    DIRECTION OUTPUT ;
    USE SIGNAL ;
    PORT
      LAYER M5 ;
        RECT  5.232 21.516 5.256 21.6 ;
    END
  END o[61]
  PIN o[62]
    DIRECTION OUTPUT ;
    USE SIGNAL ;
    PORT
      LAYER M5 ;
        RECT  5.328 21.516 5.352 21.6 ;
    END
  END o[62]
  PIN o[63]
    DIRECTION OUTPUT ;
    USE SIGNAL ;
    PORT
      LAYER M5 ;
        RECT  5.424 21.516 5.448 21.6 ;
    END
  END o[63]
  PIN o[64]
    DIRECTION OUTPUT ;
    USE SIGNAL ;
    PORT
      LAYER M5 ;
        RECT  14.736 21.516 14.76 21.6 ;
    END
  END o[64]
  PIN o[65]
    DIRECTION OUTPUT ;
    USE SIGNAL ;
    PORT
      LAYER M5 ;
        RECT  14.832 21.516 14.856 21.6 ;
    END
  END o[65]
  PIN o[66]
    DIRECTION OUTPUT ;
    USE SIGNAL ;
    PORT
      LAYER M5 ;
        RECT  14.928 21.516 14.952 21.6 ;
    END
  END o[66]
  PIN o[67]
    DIRECTION OUTPUT ;
    USE SIGNAL ;
    PORT
      LAYER M5 ;
        RECT  15.024 21.516 15.048 21.6 ;
    END
  END o[67]
  PIN o[68]
    DIRECTION OUTPUT ;
    USE SIGNAL ;
    PORT
      LAYER M5 ;
        RECT  15.12 21.516 15.144 21.6 ;
    END
  END o[68]
  PIN o[69]
    DIRECTION OUTPUT ;
    USE SIGNAL ;
    PORT
      LAYER M5 ;
        RECT  15.216 21.516 15.24 21.6 ;
    END
  END o[69]
  PIN o[6]
    DIRECTION OUTPUT ;
    USE SIGNAL ;
    PORT
      LAYER M5 ;
        RECT  6.096 21.516 6.12 21.6 ;
    END
  END o[6]
  PIN o[70]
    DIRECTION OUTPUT ;
    USE SIGNAL ;
    PORT
      LAYER M5 ;
        RECT  15.312 21.516 15.336 21.6 ;
    END
  END o[70]
  PIN o[71]
    DIRECTION OUTPUT ;
    USE SIGNAL ;
    PORT
      LAYER M5 ;
        RECT  15.408 21.516 15.432 21.6 ;
    END
  END o[71]
  PIN o[72]
    DIRECTION OUTPUT ;
    USE SIGNAL ;
    PORT
      LAYER M5 ;
        RECT  15.504 21.516 15.528 21.6 ;
    END
  END o[72]
  PIN o[73]
    DIRECTION OUTPUT ;
    USE SIGNAL ;
    PORT
      LAYER M5 ;
        RECT  15.6 21.516 15.624 21.6 ;
    END
  END o[73]
  PIN o[74]
    DIRECTION OUTPUT ;
    USE SIGNAL ;
    PORT
      LAYER M5 ;
        RECT  15.696 21.516 15.72 21.6 ;
    END
  END o[74]
  PIN o[75]
    DIRECTION OUTPUT ;
    USE SIGNAL ;
    PORT
      LAYER M5 ;
        RECT  15.792 21.516 15.816 21.6 ;
    END
  END o[75]
  PIN o[76]
    DIRECTION OUTPUT ;
    USE SIGNAL ;
    PORT
      LAYER M5 ;
        RECT  15.888 21.516 15.912 21.6 ;
    END
  END o[76]
  PIN o[77]
    DIRECTION OUTPUT ;
    USE SIGNAL ;
    PORT
      LAYER M5 ;
        RECT  15.984 21.516 16.008 21.6 ;
    END
  END o[77]
  PIN o[78]
    DIRECTION OUTPUT ;
    USE SIGNAL ;
    PORT
      LAYER M5 ;
        RECT  16.08 21.516 16.104 21.6 ;
    END
  END o[78]
  PIN o[79]
    DIRECTION OUTPUT ;
    USE SIGNAL ;
    PORT
      LAYER M5 ;
        RECT  16.176 21.516 16.2 21.6 ;
    END
  END o[79]
  PIN o[7]
    DIRECTION OUTPUT ;
    USE SIGNAL ;
    PORT
      LAYER M5 ;
        RECT  6.192 21.516 6.216 21.6 ;
    END
  END o[7]
  PIN o[80]
    DIRECTION OUTPUT ;
    USE SIGNAL ;
    PORT
      LAYER M5 ;
        RECT  16.272 21.516 16.296 21.6 ;
    END
  END o[80]
  PIN o[81]
    DIRECTION OUTPUT ;
    USE SIGNAL ;
    PORT
      LAYER M5 ;
        RECT  16.368 21.516 16.392 21.6 ;
    END
  END o[81]
  PIN o[82]
    DIRECTION OUTPUT ;
    USE SIGNAL ;
    PORT
      LAYER M5 ;
        RECT  16.464 21.516 16.488 21.6 ;
    END
  END o[82]
  PIN o[83]
    DIRECTION OUTPUT ;
    USE SIGNAL ;
    PORT
      LAYER M5 ;
        RECT  16.56 21.516 16.584 21.6 ;
    END
  END o[83]
  PIN o[84]
    DIRECTION OUTPUT ;
    USE SIGNAL ;
    PORT
      LAYER M5 ;
        RECT  16.656 21.516 16.68 21.6 ;
    END
  END o[84]
  PIN o[85]
    DIRECTION OUTPUT ;
    USE SIGNAL ;
    PORT
      LAYER M5 ;
        RECT  16.752 21.516 16.776 21.6 ;
    END
  END o[85]
  PIN o[86]
    DIRECTION OUTPUT ;
    USE SIGNAL ;
    PORT
      LAYER M5 ;
        RECT  16.848 21.516 16.872 21.6 ;
    END
  END o[86]
  PIN o[87]
    DIRECTION OUTPUT ;
    USE SIGNAL ;
    PORT
      LAYER M5 ;
        RECT  16.944 21.516 16.968 21.6 ;
    END
  END o[87]
  PIN o[88]
    DIRECTION OUTPUT ;
    USE SIGNAL ;
    PORT
      LAYER M5 ;
        RECT  17.04 21.516 17.064 21.6 ;
    END
  END o[88]
  PIN o[89]
    DIRECTION OUTPUT ;
    USE SIGNAL ;
    PORT
      LAYER M5 ;
        RECT  17.136 21.516 17.16 21.6 ;
    END
  END o[89]
  PIN o[8]
    DIRECTION OUTPUT ;
    USE SIGNAL ;
    PORT
      LAYER M5 ;
        RECT  6.288 21.516 6.312 21.6 ;
    END
  END o[8]
  PIN o[90]
    DIRECTION OUTPUT ;
    USE SIGNAL ;
    PORT
      LAYER M5 ;
        RECT  17.232 21.516 17.256 21.6 ;
    END
  END o[90]
  PIN o[91]
    DIRECTION OUTPUT ;
    USE SIGNAL ;
    PORT
      LAYER M5 ;
        RECT  17.328 21.516 17.352 21.6 ;
    END
  END o[91]
  PIN o[92]
    DIRECTION OUTPUT ;
    USE SIGNAL ;
    PORT
      LAYER M5 ;
        RECT  17.424 21.516 17.448 21.6 ;
    END
  END o[92]
  PIN o[93]
    DIRECTION OUTPUT ;
    USE SIGNAL ;
    PORT
      LAYER M5 ;
        RECT  17.52 21.516 17.544 21.6 ;
    END
  END o[93]
  PIN o[94]
    DIRECTION OUTPUT ;
    USE SIGNAL ;
    PORT
      LAYER M5 ;
        RECT  17.616 21.516 17.64 21.6 ;
    END
  END o[94]
  PIN o[95]
    DIRECTION OUTPUT ;
    USE SIGNAL ;
    PORT
      LAYER M5 ;
        RECT  17.712 21.516 17.736 21.6 ;
    END
  END o[95]
  PIN o[96]
    DIRECTION OUTPUT ;
    USE SIGNAL ;
    PORT
      LAYER M5 ;
        RECT  11.664 21.516 11.688 21.6 ;
    END
  END o[96]
  PIN o[97]
    DIRECTION OUTPUT ;
    USE SIGNAL ;
    PORT
      LAYER M5 ;
        RECT  11.76 21.516 11.784 21.6 ;
    END
  END o[97]
  PIN o[98]
    DIRECTION OUTPUT ;
    USE SIGNAL ;
    PORT
      LAYER M5 ;
        RECT  11.856 21.516 11.88 21.6 ;
    END
  END o[98]
  PIN o[99]
    DIRECTION OUTPUT ;
    USE SIGNAL ;
    PORT
      LAYER M5 ;
        RECT  11.952 21.516 11.976 21.6 ;
    END
  END o[99]
  PIN o[9]
    DIRECTION OUTPUT ;
    USE SIGNAL ;
    PORT
      LAYER M5 ;
        RECT  6.384 21.516 6.408 21.6 ;
    END
  END o[9]
  PIN rfi
    DIRECTION INPUT ;
    USE SIGNAL ;
    PORT
      LAYER M5 ;
        RECT  10.704 0 10.728 0.084 ;
    END
  END rfi
  PIN rfo
    DIRECTION OUTPUT ;
    USE SIGNAL ;
    PORT
      LAYER M5 ;
        RECT  11.568 21.516 11.592 21.6 ;
    END
  END rfo
  PIN rs
    DIRECTION INPUT ;
    USE SIGNAL ;
    PORT
      LAYER M4 ;
        RECT  0 10.608 0.084 10.632 ;
    END
  END rs
  PIN VDD
    DIRECTION INOUT ;
    USE POWER ;
    PORT
      LAYER M5 ;
        RECT  18.792 2.151 18.912 19.449 ;
        RECT  16.092 2.151 16.212 19.449 ;
        RECT  13.392 2.151 13.512 19.449 ;
        RECT  10.692 2.151 10.812 19.449 ;
        RECT  7.992 2.151 8.112 19.449 ;
        RECT  5.292 2.151 5.412 19.449 ;
        RECT  2.592 2.151 2.712 19.449 ;
    END
  END VDD
  PIN VSS
    DIRECTION INOUT ;
    USE GROUND ;
    PORT
      LAYER M5 ;
        RECT  18.6 2.137 18.72 19.463 ;
        RECT  15.9 2.137 16.02 19.463 ;
        RECT  13.2 2.137 13.32 19.463 ;
        RECT  10.5 2.137 10.62 19.463 ;
        RECT  7.8 2.137 7.92 19.463 ;
        RECT  5.1 2.137 5.22 19.463 ;
        RECT  2.4 2.137 2.52 19.463 ;
    END
  END VSS
  OBS
    LAYER RVTN ;
     RECT  2.16 2.16 19.44 2.295 ;
     RECT  2.16 2.565 19.44 2.835 ;
     RECT  2.16 3.105 19.44 3.375 ;
     RECT  2.16 3.645 19.44 3.915 ;
     RECT  2.16 4.185 19.44 4.455 ;
     RECT  2.16 4.725 19.44 4.995 ;
     RECT  2.16 5.265 19.44 5.535 ;
     RECT  2.16 5.805 19.44 6.075 ;
     RECT  2.16 6.345 19.44 6.615 ;
     RECT  2.16 6.885 19.44 7.155 ;
     RECT  2.16 7.425 19.44 7.695 ;
     RECT  2.16 7.965 19.44 8.235 ;
     RECT  2.16 8.505 19.44 8.775 ;
     RECT  2.16 9.045 19.44 9.315 ;
     RECT  2.16 9.585 19.44 9.855 ;
     RECT  2.16 10.125 19.44 10.395 ;
     RECT  2.16 10.665 19.44 10.935 ;
     RECT  2.16 11.205 19.44 11.475 ;
     RECT  2.16 11.745 19.44 12.015 ;
     RECT  2.16 12.285 19.44 12.555 ;
     RECT  2.16 12.825 19.44 13.095 ;
     RECT  2.16 13.365 19.44 13.635 ;
     RECT  2.16 13.905 19.44 14.175 ;
     RECT  2.16 14.445 19.44 14.715 ;
     RECT  2.16 14.985 19.44 15.255 ;
     RECT  2.16 15.525 19.44 15.795 ;
     RECT  2.16 16.065 19.44 16.335 ;
     RECT  2.16 16.605 19.44 16.875 ;
     RECT  2.16 17.145 19.44 17.415 ;
     RECT  2.16 17.685 19.44 17.955 ;
     RECT  2.16 18.225 19.44 18.495 ;
     RECT  2.16 18.765 19.44 19.035 ;
     RECT  2.16 19.305 19.44 19.44 ;
    LAYER RVTP ;
     RECT  2.16 2.295 19.44 2.565 ;
     RECT  2.16 2.835 19.44 3.105 ;
     RECT  2.16 3.375 19.44 3.645 ;
     RECT  2.16 3.915 19.44 4.185 ;
     RECT  2.16 4.455 19.44 4.725 ;
     RECT  2.16 4.995 19.44 5.265 ;
     RECT  2.16 5.535 19.44 5.805 ;
     RECT  2.16 6.075 19.44 6.345 ;
     RECT  2.16 6.615 19.44 6.885 ;
     RECT  2.16 7.155 19.44 7.425 ;
     RECT  2.16 7.695 19.44 7.965 ;
     RECT  2.16 8.235 19.44 8.505 ;
     RECT  2.16 8.775 19.44 9.045 ;
     RECT  2.16 9.315 19.44 9.585 ;
     RECT  2.16 9.855 19.44 10.125 ;
     RECT  2.16 10.395 19.44 10.665 ;
     RECT  2.16 10.935 19.44 11.205 ;
     RECT  2.16 11.475 19.44 11.745 ;
     RECT  2.16 12.015 19.44 12.285 ;
     RECT  2.16 12.555 19.44 12.825 ;
     RECT  2.16 13.095 19.44 13.365 ;
     RECT  2.16 13.635 19.44 13.905 ;
     RECT  2.16 14.175 19.44 14.445 ;
     RECT  2.16 14.715 19.44 14.985 ;
     RECT  2.16 15.255 19.44 15.525 ;
     RECT  2.16 15.795 19.44 16.065 ;
     RECT  2.16 16.335 19.44 16.605 ;
     RECT  2.16 16.875 19.44 17.145 ;
     RECT  2.16 17.415 19.44 17.685 ;
     RECT  2.16 17.955 19.44 18.225 ;
     RECT  2.16 18.495 19.44 18.765 ;
     RECT  2.16 19.035 19.44 19.305 ;
    LAYER M1 ;
     RECT  2.16 2.151 19.44 19.449 ;
    LAYER M2 ;
     RECT  2.16 2.151 3.271 19.449 ;
     RECT  3.271 2.106 4.847 19.449 ;
     RECT  9.751 1.152 9.959 1.17 ;
     RECT  4.847 2.151 12.271 19.449 ;
     RECT  12.271 2.034 13.307 19.449 ;
     RECT  13.307 2.151 14.539 19.449 ;
     RECT  14.539 2.106 15.755 19.449 ;
     RECT  15.755 2.151 17.887 19.449 ;
     RECT  17.887 2.106 19.139 19.449 ;
     RECT  19.139 2.151 19.44 19.449 ;
     RECT  19.44 13.986 19.463 14.004 ;
    LAYER M3 ;
     RECT  8.28 0.091 8.298 0.139 ;
     RECT  13.104 0.091 13.122 0.139 ;
     RECT  8.28 0.139 8.442 0.187 ;
     RECT  18.252 0.091 18.27 0.221 ;
     RECT  8.28 0.187 8.514 0.269 ;
     RECT  8.424 0.269 8.514 0.317 ;
     RECT  8.496 0.317 8.514 0.365 ;
     RECT  10.08 0.091 10.098 0.523 ;
     RECT  13.104 0.139 13.194 0.571 ;
     RECT  9.936 0.523 10.098 1.099 ;
     RECT  9.72 1.099 10.098 1.147 ;
     RECT  4.176 0.571 4.194 1.723 ;
     RECT  8.64 0.523 8.658 1.723 ;
     RECT  9.72 1.147 10.314 1.723 ;
     RECT  13.104 0.571 13.302 1.723 ;
     RECT  3.96 1.723 4.914 1.771 ;
     RECT  5.688 1.723 7.758 1.771 ;
     RECT  8.64 1.723 10.458 1.771 ;
     RECT  12.816 1.723 13.59 1.771 ;
     RECT  14.508 1.723 15.714 1.771 ;
     RECT  16.452 0.091 16.47 1.771 ;
     RECT  3.528 1.771 7.758 1.819 ;
     RECT  3.528 1.819 7.794 1.915 ;
     RECT  8.568 1.771 10.458 1.915 ;
     RECT  12.816 1.771 13.698 2.029 ;
     RECT  3.528 1.915 10.458 2.101 ;
     RECT  3.276 2.101 10.458 2.143 ;
     RECT  17.82 1.723 18.378 2.143 ;
     RECT  19.116 2.101 19.134 2.143 ;
     RECT  3.276 2.143 10.605 2.191 ;
     RECT  12.276 2.029 13.698 2.191 ;
     RECT  14.508 1.771 16.47 2.191 ;
     RECT  17.82 2.143 19.134 2.191 ;
     RECT  3.276 2.191 10.674 2.263 ;
     RECT  3.276 2.263 11.358 2.371 ;
     RECT  12.276 2.191 19.134 2.371 ;
     RECT  2.415 2.143 2.505 2.413 ;
     RECT  3.276 2.371 19.242 2.413 ;
     RECT  2.415 2.413 19.242 2.641 ;
     RECT  2.415 2.641 19.422 10.603 ;
     RECT  2.304 10.603 19.422 10.895 ;
     RECT  2.415 10.895 19.422 13.981 ;
     RECT  2.415 13.981 19.458 15.025 ;
     RECT  2.34 15.025 19.458 16.951 ;
     RECT  2.304 16.951 19.458 17.879 ;
     RECT  2.376 17.879 19.458 18.689 ;
     RECT  2.415 18.689 19.458 19.229 ;
     RECT  14.904 19.229 18.705 19.265 ;
     RECT  2.415 19.229 3.69 19.301 ;
     RECT  4.788 19.229 14.058 19.301 ;
     RECT  14.904 19.265 17.874 19.301 ;
     RECT  14.904 19.301 17.586 19.325 ;
     RECT  2.415 19.301 3.582 19.337 ;
     RECT  5.115 19.301 14.058 19.373 ;
     RECT  14.904 19.325 15.066 19.373 ;
     RECT  15.915 19.325 17.586 19.373 ;
     RECT  5.115 19.373 6.534 19.409 ;
     RECT  2.415 19.337 3.474 19.457 ;
     RECT  5.115 19.409 5.778 19.457 ;
     RECT  9.828 19.373 13.59 19.457 ;
     RECT  15.915 19.373 16.47 19.457 ;
     RECT  18.615 19.265 18.705 19.457 ;
     RECT  11.232 19.457 13.59 19.469 ;
     RECT  9.828 19.457 10.17 19.565 ;
     RECT  12.492 19.469 13.59 19.565 ;
     RECT  16.452 19.457 16.47 19.565 ;
     RECT  7.668 19.373 8.874 19.613 ;
     RECT  12.492 19.565 13.554 19.613 ;
     RECT  8.568 19.613 8.874 19.661 ;
     RECT  13.536 19.613 13.554 19.949 ;
     RECT  5.724 19.457 5.778 19.997 ;
     RECT  7.668 19.613 7.686 19.997 ;
     RECT  14.904 19.373 14.922 19.997 ;
     RECT  8.82 19.661 8.874 20.285 ;
     RECT  9.828 19.565 9.954 20.477 ;
     RECT  2.772 19.457 3.474 20.525 ;
     RECT  9.828 20.477 9.846 20.525 ;
     RECT  12.492 19.613 12.51 20.525 ;
     RECT  18 20.395 18.018 20.525 ;
     RECT  19.44 19.229 19.458 20.525 ;
     RECT  5.76 19.997 5.778 20.573 ;
     RECT  11.484 19.469 11.502 21.019 ;
     RECT  11.484 21.019 11.79 21.197 ;
     RECT  16.416 21.115 16.434 21.293 ;
     RECT  2.772 20.525 3.114 21.485 ;
     RECT  5.076 21.355 5.094 21.485 ;
     RECT  6.516 19.409 6.534 21.485 ;
     RECT  8.856 20.285 8.874 21.485 ;
     RECT  11.484 21.197 11.502 21.485 ;
    LAYER M4 ;
     RECT  0.06 10.512 0.179 10.632 ;
     RECT  0.133 7.92 2.408 7.944 ;
     RECT  0.179 10.608 2.408 10.632 ;
     RECT  2.293 16.56 2.408 16.584 ;
     RECT  2.408 2.148 2.512 19.452 ;
     RECT  2.293 21.456 2.533 21.48 ;
     RECT  2.512 2.418 2.704 19.452 ;
     RECT  2.704 13.008 2.725 19.452 ;
     RECT  2.725 13.008 2.837 19.56 ;
     RECT  2.837 13.008 2.867 18.984 ;
     RECT  2.867 16.752 2.905 18.984 ;
     RECT  2.867 13.008 3.097 14.952 ;
     RECT  2.533 21.216 3.125 21.48 ;
     RECT  2.905 18.24 3.347 18.984 ;
     RECT  3.097 13.008 3.377 13.56 ;
     RECT  3.397 20.496 3.485 20.52 ;
     RECT  3.377 13.536 3.629 13.56 ;
     RECT  3.347 18.24 3.683 18.84 ;
     RECT  2.704 6.816 3.701 6.84 ;
     RECT  3.517 1.776 3.781 1.8 ;
     RECT  2.905 16.752 3.877 17.112 ;
     RECT  3.097 14.928 3.989 14.952 ;
     RECT  2.704 11.952 4.025 11.976 ;
     RECT  3.805 5.856 4.201 6.696 ;
     RECT  4.165 0.576 4.249 0.6 ;
     RECT  2.704 4.032 4.273 4.536 ;
     RECT  4.201 5.76 4.273 6.696 ;
     RECT  3.985 2.976 4.357 3 ;
     RECT  3.877 16.512 4.453 17.112 ;
     RECT  4.453 16.416 4.549 17.112 ;
     RECT  4.357 2.88 4.561 3 ;
     RECT  4.273 4.032 4.561 6.696 ;
     RECT  3.781 1.728 4.604 1.8 ;
     RECT  4.561 2.88 4.604 6.696 ;
     RECT  4.604 1.728 4.669 6.696 ;
     RECT  3.697 10.224 4.741 10.248 ;
     RECT  4.165 15.312 4.837 15.384 ;
     RECT  4.549 16.368 4.837 17.112 ;
     RECT  4.069 12.48 4.892 12.504 ;
     RECT  4.981 21.36 5.021 21.384 ;
     RECT  4.885 0.144 5.075 0.168 ;
     RECT  4.669 1.728 5.108 6.84 ;
     RECT  2.704 7.92 5.108 7.944 ;
     RECT  4.981 9.072 5.108 9.096 ;
     RECT  4.741 10.224 5.108 10.824 ;
     RECT  4.892 12.48 5.108 13.464 ;
     RECT  4.837 15.312 5.108 17.112 ;
     RECT  3.683 18.24 5.108 18.792 ;
     RECT  5.108 1.728 5.317 19.452 ;
     RECT  5.021 21.36 5.317 21.48 ;
     RECT  5.317 1.728 5.404 21.48 ;
     RECT  5.221 0.192 5.413 0.36 ;
     RECT  5.404 1.728 5.465 9.096 ;
     RECT  5.413 0.192 5.603 0.456 ;
     RECT  5.465 2.88 5.681 9.096 ;
     RECT  5.603 0.192 5.699 0.216 ;
     RECT  5.681 3.36 5.753 9.096 ;
     RECT  5.404 14.16 5.843 21.48 ;
     RECT  5.465 1.728 6.049 1.8 ;
     RECT  5.753 3.36 6.227 8.52 ;
     RECT  6.227 3.984 7.153 8.52 ;
     RECT  5.843 14.16 7.297 17.64 ;
     RECT  5.843 18.816 7.297 21.48 ;
     RECT  6.049 1.728 7.3 1.752 ;
     RECT  7.153 3.984 7.405 9.288 ;
     RECT  7.3 1.728 7.408 1.8 ;
     RECT  6.829 2.88 7.477 2.904 ;
     RECT  7.405 3.936 7.477 9.288 ;
     RECT  7.573 0.24 7.669 0.264 ;
     RECT  7.408 1.728 7.808 1.848 ;
     RECT  7.477 2.88 7.808 9.288 ;
     RECT  5.404 12.528 7.808 12.552 ;
     RECT  7.297 14.16 7.808 21.48 ;
     RECT  7.669 0.144 8.101 0.264 ;
     RECT  7.808 1.728 8.104 21.48 ;
     RECT  8.104 16.368 8.165 21.48 ;
     RECT  8.104 1.728 8.201 9.336 ;
     RECT  8.101 0.144 8.242 0.312 ;
     RECT  8.104 14.832 8.309 14.856 ;
     RECT  8.242 0.096 8.341 0.312 ;
     RECT  8.341 0.096 8.353 0.36 ;
     RECT  8.165 16.416 8.417 21.48 ;
     RECT  8.353 0.144 8.486 0.36 ;
     RECT  8.486 0.192 8.569 0.36 ;
     RECT  8.417 17.616 8.597 21.48 ;
     RECT  8.201 1.728 8.723 1.896 ;
     RECT  8.201 2.88 8.813 9.336 ;
     RECT  8.597 20.256 8.849 21.48 ;
     RECT  8.849 20.448 8.885 21.48 ;
     RECT  8.629 0.528 8.915 0.552 ;
     RECT  8.813 2.88 8.921 9.288 ;
     RECT  8.723 1.728 9.692 1.848 ;
     RECT  8.885 20.448 9.857 20.52 ;
     RECT  9.692 1.104 9.884 1.848 ;
     RECT  9.884 0.528 9.889 1.848 ;
     RECT  8.921 3.408 9.889 9.144 ;
     RECT  9.857 20.448 9.965 20.472 ;
     RECT  9.889 0.528 10.069 9.144 ;
     RECT  8.597 17.616 10.141 18.984 ;
     RECT  10.069 0.096 10.261 9.144 ;
     RECT  10.261 0.096 10.355 9.768 ;
     RECT  10.355 0.192 10.451 9.768 ;
     RECT  10.451 1.728 10.508 9.768 ;
     RECT  9.925 11.136 10.508 11.16 ;
     RECT  8.417 16.416 10.508 16.44 ;
     RECT  10.141 17.616 10.508 19.56 ;
     RECT  10.451 0.192 10.547 0.216 ;
     RECT  10.508 1.728 10.643 19.56 ;
     RECT  10.643 1.824 10.739 19.56 ;
     RECT  10.739 2.418 10.804 19.56 ;
     RECT  10.804 18.24 10.835 19.56 ;
     RECT  10.835 18.24 11.017 19.464 ;
     RECT  10.804 2.784 11.045 9.672 ;
     RECT  10.804 16.56 11.161 17.064 ;
     RECT  11.429 21.456 11.513 21.48 ;
     RECT  11.045 3.072 11.693 9.672 ;
     RECT  11.557 20.928 11.801 21.192 ;
     RECT  10.804 10.8 11.809 11.16 ;
     RECT  11.801 20.928 11.843 21.048 ;
     RECT  11.017 18.768 11.891 19.464 ;
     RECT  11.933 14.784 12.017 14.808 ;
     RECT  11.797 16.512 12.017 16.536 ;
     RECT  12.157 17.04 12.193 17.448 ;
     RECT  11.891 18.768 12.193 19.416 ;
     RECT  11.809 11.136 12.197 11.16 ;
     RECT  11.693 3.264 12.233 9.048 ;
     RECT  12.325 20.496 12.521 20.52 ;
     RECT  12.121 15.888 12.997 16.008 ;
     RECT  12.193 17.04 13.057 19.416 ;
     RECT  12.997 15.84 13.093 16.008 ;
     RECT  13.057 17.04 13.093 19.944 ;
     RECT  13.093 0.096 13.165 0.12 ;
     RECT  12.805 1.728 13.208 1.752 ;
     RECT  12.233 3.552 13.208 9.048 ;
     RECT  12.373 11.376 13.208 11.4 ;
     RECT  12.869 13.2 13.208 13.224 ;
     RECT  13.093 15.84 13.208 19.944 ;
     RECT  13.165 0.096 13.273 0.168 ;
     RECT  13.273 0.096 13.357 0.6 ;
     RECT  13.285 21.168 13.429 21.192 ;
     RECT  13.208 1.728 13.504 19.944 ;
     RECT  13.357 0.096 13.523 0.12 ;
     RECT  13.504 15.36 13.565 19.944 ;
     RECT  13.565 15.36 13.601 19.56 ;
     RECT  13.429 21.168 13.619 21.432 ;
     RECT  13.619 21.312 13.667 21.432 ;
     RECT  13.504 1.728 13.753 1.8 ;
     RECT  13.667 21.408 14.051 21.432 ;
     RECT  13.601 15.36 14.501 19.368 ;
     RECT  13.504 2.88 14.677 9 ;
     RECT  14.501 15.984 14.893 19.368 ;
     RECT  13.504 12.48 14.933 13.08 ;
     RECT  14.677 2.88 15.001 9.096 ;
     RECT  14.933 13.056 15.013 13.08 ;
     RECT  15.001 2.88 15.101 9.72 ;
     RECT  14.485 10.8 15.101 10.824 ;
     RECT  15.101 2.88 15.109 10.824 ;
     RECT  14.893 15.984 15.155 19.992 ;
     RECT  15.013 13.056 15.205 13.368 ;
     RECT  14.629 14.832 15.205 14.856 ;
     RECT  13.753 1.728 15.397 1.752 ;
     RECT  15.397 1.728 15.505 1.8 ;
     RECT  15.205 13.056 15.677 14.856 ;
     RECT  15.155 15.984 15.677 19.452 ;
     RECT  15.505 1.728 15.725 1.848 ;
     RECT  15.589 20.496 15.733 20.52 ;
     RECT  15.725 1.776 15.749 1.848 ;
     RECT  15.109 2.88 15.749 11.016 ;
     RECT  15.749 1.776 15.797 11.016 ;
     RECT  15.797 1.824 15.869 11.016 ;
     RECT  15.869 2.016 15.908 11.016 ;
     RECT  15.677 13.056 15.908 19.452 ;
     RECT  15.908 2.016 15.923 19.452 ;
     RECT  15.923 2.148 16.012 19.452 ;
     RECT  15.973 0.528 16.069 0.552 ;
     RECT  16.069 0.528 16.165 0.648 ;
     RECT  16.012 2.418 16.204 19.452 ;
     RECT  16.204 13.632 16.213 19.452 ;
     RECT  15.733 20.496 16.213 21.432 ;
     RECT  16.165 0.336 16.357 0.648 ;
     RECT  16.357 0.192 16.403 0.648 ;
     RECT  16.403 0.192 16.412 0.456 ;
     RECT  16.204 2.418 16.481 11.016 ;
     RECT  16.213 13.632 16.481 21.432 ;
     RECT  16.412 0.096 16.499 0.456 ;
     RECT  16.481 20.4 16.499 21.432 ;
     RECT  16.499 0.192 16.547 0.216 ;
     RECT  16.499 20.4 16.547 21.24 ;
     RECT  16.481 2.418 16.625 10.344 ;
     RECT  16.625 2.418 16.661 10.248 ;
     RECT  16.661 2.418 16.877 9.768 ;
     RECT  16.481 13.632 16.877 19.368 ;
     RECT  16.877 13.632 17.093 18.888 ;
     RECT  16.877 2.418 17.125 9.528 ;
     RECT  17.093 15.36 17.317 18.888 ;
     RECT  16.204 12.192 17.377 12.216 ;
     RECT  17.377 12.192 17.509 12.552 ;
     RECT  17.093 13.632 17.509 14.232 ;
     RECT  17.509 12.192 17.525 14.232 ;
     RECT  17.317 15.36 17.597 17.784 ;
     RECT  17.125 2.256 17.765 9.528 ;
     RECT  16.547 20.4 18.029 20.52 ;
     RECT  18.133 0.192 18.181 0.216 ;
     RECT  18.181 0.096 18.229 0.216 ;
     RECT  18.229 0.096 18.281 0.264 ;
     RECT  17.597 15.936 18.313 17.784 ;
     RECT  17.317 18.816 18.313 18.888 ;
     RECT  17.765 1.728 18.332 9.528 ;
     RECT  18.332 1.728 18.389 9.672 ;
     RECT  18.389 2.148 18.608 9.672 ;
     RECT  17.525 12.192 18.608 13.656 ;
     RECT  18.313 15.936 18.608 18.888 ;
     RECT  18.608 2.148 18.712 19.452 ;
     RECT  18.712 2.418 18.904 19.182 ;
     RECT  18.281 0.144 19.043 0.264 ;
     RECT  18.904 18.24 19.043 18.84 ;
     RECT  18.904 4.56 19.073 4.68 ;
     RECT  18.904 6.288 19.091 6.312 ;
     RECT  19.043 0.24 19.139 0.264 ;
     RECT  19.073 4.656 19.153 4.68 ;
     RECT  18.904 9.648 19.283 9.672 ;
     RECT  19.043 18.816 19.283 18.84 ;
     RECT  18.029 20.496 19.469 20.52 ;
    LAYER M5 ;
     RECT  13.008 0.016 19.08 0.229 ;
     RECT  3.792 0.016 10.728 1.763 ;
     RECT  13.008 0.229 19.128 1.763 ;
     RECT  3.888 1.763 10.728 1.811 ;
     RECT  2.4 2.137 2.52 2.151 ;
     RECT  4.368 1.811 10.728 2.151 ;
     RECT  4.368 2.151 10.812 2.915 ;
     RECT  4.464 2.915 10.812 2.963 ;
     RECT  13.2 1.763 19.128 3.443 ;
     RECT  4.896 2.963 10.812 3.539 ;
     RECT  13.2 3.443 14.76 3.587 ;
     RECT  15.792 3.443 19.128 3.875 ;
     RECT  5.1 3.539 10.812 3.971 ;
     RECT  5.1 3.971 9.528 4.115 ;
     RECT  15.9 3.875 19.128 4.691 ;
     RECT  13.2 3.587 14.376 4.933 ;
     RECT  15.9 4.691 19.08 4.933 ;
     RECT  13.2 4.933 19.08 5.075 ;
     RECT  13.2 5.075 14.376 5.219 ;
     RECT  13.2 5.219 14.28 5.267 ;
     RECT  5.1 4.115 6.216 5.317 ;
     RECT  7.2 4.115 9.528 5.317 ;
     RECT  5.1 5.317 9.528 5.747 ;
     RECT  15.9 5.075 19.08 6.085 ;
     RECT  15.792 6.085 19.08 6.229 ;
     RECT  12.096 4.933 12.12 6.277 ;
     RECT  15.408 6.229 19.08 6.323 ;
     RECT  12.096 6.277 12.216 6.709 ;
     RECT  12 6.709 12.216 6.757 ;
     RECT  13.2 5.267 13.656 6.757 ;
     RECT  2.4 2.151 2.712 6.805 ;
     RECT  15.408 6.323 18.912 6.805 ;
     RECT  5.1 5.747 6.456 7.189 ;
     RECT  7.8 5.747 9.528 7.189 ;
     RECT  12 6.757 13.656 7.381 ;
     RECT  5.1 7.189 9.528 7.717 ;
     RECT  10.5 3.971 10.812 7.717 ;
     RECT  11.952 7.381 13.656 7.909 ;
     RECT  11.952 7.909 13.848 8.291 ;
     RECT  15.024 6.805 18.912 8.435 ;
     RECT  12.48 8.291 13.848 8.581 ;
     RECT  5.1 7.717 10.812 9.061 ;
     RECT  4.992 9.061 10.812 9.637 ;
     RECT  15.792 8.435 18.912 9.637 ;
     RECT  4.992 9.637 10.968 9.779 ;
     RECT  12.48 8.581 14.808 10.165 ;
     RECT  15.792 9.637 19.272 10.165 ;
     RECT  4.992 9.779 9.528 10.259 ;
     RECT  0.144 7.909 0.168 10.547 ;
     RECT  10.5 9.779 10.968 10.789 ;
     RECT  12.48 10.165 19.272 10.789 ;
     RECT  5.1 10.259 9.528 11.125 ;
     RECT  10.5 10.789 19.272 11.125 ;
     RECT  2.4 6.805 3.672 12.469 ;
     RECT  2.4 12.469 4.104 13.429 ;
     RECT  5.1 11.125 19.272 13.429 ;
     RECT  2.4 13.429 19.272 16.549 ;
     RECT  2.304 16.549 19.272 18.851 ;
     RECT  9.936 18.851 18.912 18.995 ;
     RECT  10.5 18.995 18.912 19.449 ;
     RECT  10.5 19.449 18.72 19.463 ;
     RECT  10.8 19.463 17.928 20.531 ;
     RECT  2.304 18.851 8.52 21.491 ;
     RECT  2.448 21.491 8.52 21.584 ;
     RECT  10.8 20.531 17.736 21.584 ;
  END
END hbfd_rly_136_SN_rfc
END LIBRARY
